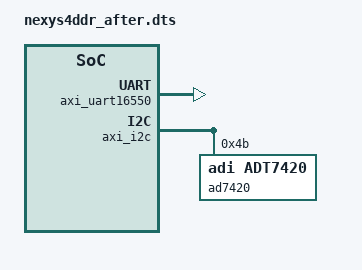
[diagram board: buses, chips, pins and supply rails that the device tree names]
	axi_uart16550: serial@10400000 {
		compatible = "ns16550a";
		reg = <0x10400000 0x10000>;

		reg-shift = <2>;
		reg-offset = <0x1000>;

		clocks	= <&ext>;

		interrupt-parent = <&axi_intc>;
		interrupts = <0>;
	};

	axi_i2c: i2c@10a00000 {
	    compatible = "xlnx,xps-iic-2.00.a";
	    interrupt-parent = <&axi_intc>;
	    interrupts = <4>;
	    reg = < 0x10a00000 0x10000 >;
	    clocks = <&ext>;
	    xlnx,clk-freq = <0x5f5e100>;
	    xlnx,family = "Artix7";
	    xlnx,gpo-width = <0x1>;
	    xlnx,iic-freq = <0x186a0>;
	    xlnx,scl-inertial-delay = <0x0>;
	    xlnx,sda-inertial-delay = <0x0>;
	    xlnx,ten-bit-adr = <0x0>;
	    #address-cells = <1>;
	    #size-cells = <0>;

	    ad7420@4b {
		compatible = "adi,adt7420";
		reg = <0x4b>;
	    };
	} ;
};

&ext {
	clock-frequency = <50000000>;
};
	axi_i2c: i2c@10a00000 {
	    compatible = "xlnx,xps-iic-2.00.a";
	    interrupt-parent = <&axi_intc>;
	    interrupts = <4>;
	    reg = < 0x10a00000 0x10000 >;
	    clocks = <&ext>;
	    xlnx,clk-freq = <0x5f5e100>;
	    xlnx,family = "Artix7";
	    xlnx,gpo-width = <0x1>;
	    xlnx,iic-freq = <0x186a0>;
	    xlnx,scl-inertial-delay = <0x0>;
	    xlnx,sda-inertial-delay = <0x0>;
	    xlnx,ten-bit-adr = <0x0>;
	    #address-cells = <1>;
	    #size-cells = <0>;

	    ad7420@4b {
		compatible = "adi,adt7420";
		reg = <0x4b>;
	    };
	} ;
};

&ext {
	clock-frequency = <50000000>;
};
